VERSION 5.7 ;

  DIVIDERCHAR "/" ;
  BUSBITCHARS "[]" ;
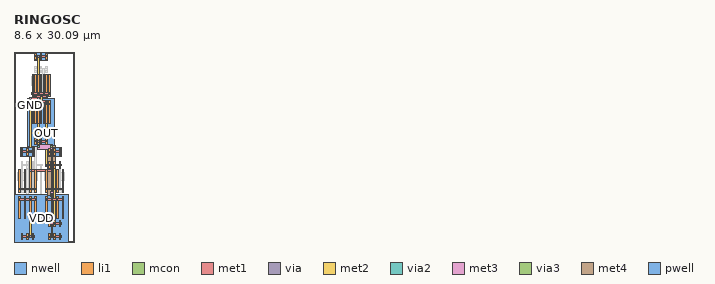
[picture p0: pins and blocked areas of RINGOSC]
MACRO RINGOSC
  CLASS BLOCK ;
  FOREIGN RINGOSC ;
  ORIGIN 0.000 0.000 ;
  SIZE 8.600 BY 30.090 ;
  PIN VDD
    ANTENNADIFFAREA 5.147100 ;
    PORT
      LAYER nwell ;
        RECT 2.150 15.120 6.450 22.680 ;
        RECT 0.000 0.000 8.600 7.560 ;
      LAYER li1 ;
        RECT 2.885 18.815 3.135 22.345 ;
        RECT 3.745 18.815 3.995 22.345 ;
        RECT 4.605 18.815 4.855 22.345 ;
        RECT 5.465 18.815 5.715 22.345 ;
        RECT 3.315 15.455 3.565 16.465 ;
        RECT 4.175 15.455 4.425 16.465 ;
        RECT 5.035 15.455 5.285 16.465 ;
        RECT 0.735 3.695 0.985 7.225 ;
        RECT 1.595 3.695 1.845 7.225 ;
        RECT 2.455 3.695 2.705 7.225 ;
        RECT 3.315 3.695 3.565 7.225 ;
        RECT 5.035 3.695 5.285 7.225 ;
        RECT 5.895 3.695 6.145 7.225 ;
        RECT 6.755 3.695 7.005 7.225 ;
        RECT 7.615 3.695 7.865 7.225 ;
        RECT 1.165 0.335 1.415 1.345 ;
        RECT 2.025 0.335 2.275 1.345 ;
        RECT 2.885 0.335 3.135 1.345 ;
        RECT 5.465 0.335 5.715 1.345 ;
        RECT 6.325 0.335 6.575 1.345 ;
        RECT 7.185 0.335 7.435 1.345 ;
      LAYER mcon ;
        RECT 2.925 21.755 3.095 21.925 ;
        RECT 3.785 21.755 3.955 21.925 ;
        RECT 4.645 21.755 4.815 21.925 ;
        RECT 5.505 21.755 5.675 21.925 ;
        RECT 3.355 15.875 3.525 16.045 ;
        RECT 4.215 15.875 4.385 16.045 ;
        RECT 5.075 15.875 5.245 16.045 ;
        RECT 0.775 6.635 0.945 6.805 ;
        RECT 1.635 6.635 1.805 6.805 ;
        RECT 2.495 6.635 2.665 6.805 ;
        RECT 3.355 6.635 3.525 6.805 ;
        RECT 5.075 6.635 5.245 6.805 ;
        RECT 5.935 6.635 6.105 6.805 ;
        RECT 6.795 6.635 6.965 6.805 ;
        RECT 7.655 6.635 7.825 6.805 ;
        RECT 1.205 0.755 1.375 0.925 ;
        RECT 2.065 0.755 2.235 0.925 ;
        RECT 2.925 0.755 3.095 0.925 ;
        RECT 5.505 0.755 5.675 0.925 ;
        RECT 6.365 0.755 6.535 0.925 ;
        RECT 7.225 0.755 7.395 0.925 ;
      LAYER met1 ;
        RECT 2.840 21.700 5.760 21.980 ;
        RECT 3.270 15.820 5.330 16.100 ;
        RECT 0.690 6.580 3.610 6.860 ;
        RECT 4.990 6.580 7.910 6.860 ;
        RECT 2.420 3.640 6.180 3.920 ;
        RECT 1.120 0.700 3.180 0.980 ;
        RECT 5.420 0.700 7.480 0.980 ;
      LAYER via ;
        RECT 3.740 21.710 4.000 21.970 ;
        RECT 3.740 15.830 4.000 16.090 ;
        RECT 2.450 6.590 2.710 6.850 ;
        RECT 5.890 6.590 6.150 6.850 ;
        RECT 2.450 3.650 2.710 3.910 ;
        RECT 5.890 3.650 6.150 3.910 ;
        RECT 2.450 0.710 2.710 0.970 ;
        RECT 5.890 0.710 6.150 0.970 ;
      LAYER met2 ;
        RECT 3.730 14.935 4.010 22.000 ;
        RECT 2.440 0.680 2.720 6.880 ;
        RECT 5.880 0.680 6.160 7.745 ;
      LAYER via2 ;
        RECT 3.730 14.980 4.010 15.260 ;
        RECT 5.880 7.420 6.160 7.700 ;
      LAYER met3 ;
        RECT 3.705 14.720 6.085 15.520 ;
        RECT 5.755 7.160 6.185 7.960 ;
      LAYER via3 ;
        RECT 5.760 14.960 6.080 15.280 ;
        RECT 5.760 7.400 6.080 7.720 ;
      LAYER met4 ;
        RECT 5.330 7.395 6.510 15.285 ;
    END
  END VDD
  PIN OUT
    ANTENNAGATEAREA 1.890000 ;
    ANTENNADIFFAREA 1.764000 ;
    PORT
      LAYER li1 ;
        RECT 3.315 23.015 3.565 26.545 ;
        RECT 4.175 23.015 4.425 26.545 ;
        RECT 5.035 23.015 5.285 26.545 ;
        RECT 3.315 18.815 3.565 22.345 ;
        RECT 4.175 18.815 4.425 22.345 ;
        RECT 5.035 18.815 5.285 22.345 ;
        RECT 5.465 11.675 5.715 12.685 ;
        RECT 6.325 11.675 6.575 12.685 ;
        RECT 7.185 11.675 7.435 12.685 ;
        RECT 5.465 2.435 5.715 3.445 ;
        RECT 6.325 2.435 6.575 3.445 ;
        RECT 7.185 2.435 7.435 3.445 ;
      LAYER mcon ;
        RECT 3.355 23.015 3.525 23.185 ;
        RECT 4.215 23.015 4.385 23.185 ;
        RECT 5.075 23.015 5.245 23.185 ;
        RECT 3.355 22.175 3.525 22.345 ;
        RECT 4.215 22.175 4.385 22.345 ;
        RECT 5.075 22.175 5.245 22.345 ;
        RECT 5.505 12.095 5.675 12.265 ;
        RECT 6.365 12.095 6.535 12.265 ;
        RECT 7.225 12.095 7.395 12.265 ;
        RECT 5.505 2.855 5.675 3.025 ;
        RECT 6.365 2.855 6.535 3.025 ;
        RECT 7.225 2.855 7.395 3.025 ;
      LAYER met1 ;
        RECT 3.270 22.960 5.330 23.240 ;
        RECT 3.270 22.120 5.330 22.400 ;
        RECT 5.000 12.040 7.480 12.320 ;
        RECT 5.420 2.800 7.480 3.080 ;
      LAYER via ;
        RECT 4.170 22.970 4.430 23.230 ;
        RECT 4.170 22.130 4.430 22.390 ;
        RECT 5.030 22.130 5.290 22.390 ;
        RECT 5.030 12.050 5.290 12.310 ;
        RECT 6.320 12.050 6.580 12.310 ;
        RECT 6.320 2.810 6.580 3.070 ;
      LAYER met2 ;
        RECT 4.160 22.100 4.440 23.260 ;
        RECT 5.020 12.020 5.300 22.420 ;
        RECT 6.310 2.780 6.590 12.340 ;
    END
  END OUT
  PIN GND
    ANTENNADIFFAREA 5.147100 ;
    PORT
      LAYER pwell ;
        RECT 3.225 28.710 5.375 30.090 ;
        RECT 1.075 13.590 3.225 14.970 ;
        RECT 5.375 13.590 7.525 14.970 ;
      LAYER li1 ;
        RECT 3.315 28.895 3.565 29.905 ;
        RECT 4.175 28.895 4.425 29.905 ;
        RECT 5.035 28.895 5.285 29.905 ;
        RECT 2.885 23.015 3.135 26.545 ;
        RECT 3.745 23.015 3.995 26.545 ;
        RECT 4.605 23.015 4.855 26.545 ;
        RECT 5.465 23.015 5.715 26.545 ;
        RECT 1.165 13.775 1.415 14.785 ;
        RECT 2.025 13.775 2.275 14.785 ;
        RECT 2.885 13.775 3.135 14.785 ;
        RECT 5.465 13.775 5.715 14.785 ;
        RECT 6.325 13.775 6.575 14.785 ;
        RECT 7.185 13.775 7.435 14.785 ;
        RECT 0.735 7.895 0.985 11.425 ;
        RECT 1.595 7.895 1.845 11.425 ;
        RECT 2.455 7.895 2.705 11.425 ;
        RECT 3.315 7.895 3.565 11.425 ;
        RECT 5.035 7.895 5.285 11.425 ;
        RECT 5.895 7.895 6.145 11.425 ;
        RECT 6.755 7.895 7.005 11.425 ;
        RECT 7.615 7.895 7.865 11.425 ;
      LAYER mcon ;
        RECT 3.355 29.315 3.525 29.485 ;
        RECT 4.215 29.315 4.385 29.485 ;
        RECT 5.075 29.315 5.245 29.485 ;
        RECT 2.925 23.435 3.095 23.605 ;
        RECT 3.785 23.435 3.955 23.605 ;
        RECT 4.645 23.435 4.815 23.605 ;
        RECT 5.505 23.435 5.675 23.605 ;
        RECT 1.205 14.195 1.375 14.365 ;
        RECT 2.065 14.195 2.235 14.365 ;
        RECT 2.925 14.195 3.095 14.365 ;
        RECT 5.505 14.195 5.675 14.365 ;
        RECT 6.365 14.195 6.535 14.365 ;
        RECT 7.225 14.195 7.395 14.365 ;
        RECT 0.775 8.315 0.945 8.485 ;
        RECT 1.635 8.315 1.805 8.485 ;
        RECT 2.495 8.315 2.665 8.485 ;
        RECT 3.355 8.315 3.525 8.485 ;
        RECT 5.075 8.315 5.245 8.485 ;
        RECT 5.935 8.315 6.105 8.485 ;
        RECT 6.795 8.315 6.965 8.485 ;
        RECT 7.655 8.315 7.825 8.485 ;
      LAYER met1 ;
        RECT 3.270 29.260 5.330 29.540 ;
        RECT 2.840 23.380 5.760 23.660 ;
        RECT 2.420 22.540 4.030 22.820 ;
        RECT 1.120 14.140 3.180 14.420 ;
        RECT 5.420 14.140 7.480 14.420 ;
        RECT 2.420 11.200 6.180 11.480 ;
        RECT 0.690 8.260 3.610 8.540 ;
        RECT 4.990 8.260 7.910 8.540 ;
      LAYER via ;
        RECT 3.740 29.270 4.000 29.530 ;
        RECT 3.740 23.390 4.000 23.650 ;
        RECT 2.450 22.550 2.710 22.810 ;
        RECT 3.740 22.550 4.000 22.810 ;
        RECT 2.450 14.150 2.710 14.410 ;
        RECT 5.890 14.150 6.150 14.410 ;
        RECT 2.450 11.210 2.710 11.470 ;
        RECT 5.890 11.210 6.150 11.470 ;
        RECT 2.450 8.270 2.710 8.530 ;
        RECT 5.890 8.270 6.150 8.530 ;
      LAYER met2 ;
        RECT 2.440 8.240 2.720 22.840 ;
        RECT 3.730 22.520 4.010 29.560 ;
        RECT 5.880 8.240 6.160 14.440 ;
    END
  END GND
  OBS
      LAYER pwell ;
        RECT 2.755 24.860 5.845 26.170 ;
        RECT 0.605 9.740 3.695 11.050 ;
        RECT 4.905 9.740 7.995 11.050 ;
      LAYER li1 ;
        RECT 3.315 26.795 3.565 27.805 ;
        RECT 4.175 26.795 4.425 27.805 ;
        RECT 5.035 26.795 5.285 27.805 ;
        RECT 3.315 17.555 3.565 18.565 ;
        RECT 4.175 17.555 4.425 18.565 ;
        RECT 5.035 17.555 5.285 18.565 ;
        RECT 1.165 11.675 1.415 12.685 ;
        RECT 2.025 11.675 2.275 12.685 ;
        RECT 2.885 11.675 3.135 12.685 ;
        RECT 1.165 7.895 1.415 11.425 ;
        RECT 2.025 7.895 2.275 11.425 ;
        RECT 2.885 7.895 3.135 11.425 ;
        RECT 1.165 3.695 1.415 7.225 ;
        RECT 2.025 3.695 2.275 7.225 ;
        RECT 2.885 3.695 3.135 7.225 ;
        RECT 1.165 2.435 1.415 3.445 ;
        RECT 2.025 2.435 2.275 3.445 ;
        RECT 2.885 2.435 3.135 3.445 ;
        RECT 4.175 2.855 4.425 12.265 ;
        RECT 5.465 7.895 5.715 11.425 ;
        RECT 6.325 7.895 6.575 11.425 ;
        RECT 7.185 7.895 7.435 11.425 ;
        RECT 5.465 3.695 5.715 7.225 ;
        RECT 6.325 3.695 6.575 7.225 ;
        RECT 7.185 3.695 7.435 7.225 ;
      LAYER mcon ;
        RECT 3.355 27.215 3.525 27.385 ;
        RECT 4.215 27.215 4.385 27.385 ;
        RECT 5.075 27.215 5.245 27.385 ;
        RECT 3.355 17.975 3.525 18.145 ;
        RECT 4.215 17.975 4.385 18.145 ;
        RECT 5.075 17.975 5.245 18.145 ;
        RECT 1.205 12.095 1.375 12.265 ;
        RECT 2.065 12.095 2.235 12.265 ;
        RECT 2.925 12.095 3.095 12.265 ;
        RECT 4.215 12.095 4.385 12.265 ;
        RECT 1.205 7.895 1.375 8.065 ;
        RECT 2.065 7.895 2.235 8.065 ;
        RECT 2.925 7.895 3.095 8.065 ;
        RECT 5.505 7.895 5.675 8.065 ;
        RECT 6.365 7.895 6.535 8.065 ;
        RECT 7.225 7.895 7.395 8.065 ;
        RECT 1.205 7.055 1.375 7.225 ;
        RECT 2.065 7.055 2.235 7.225 ;
        RECT 2.925 7.055 3.095 7.225 ;
        RECT 4.215 7.055 4.385 7.225 ;
        RECT 1.205 2.855 1.375 3.025 ;
        RECT 2.065 2.855 2.235 3.025 ;
        RECT 2.925 2.855 3.095 3.025 ;
        RECT 5.505 7.055 5.675 7.225 ;
        RECT 6.365 7.055 6.535 7.225 ;
        RECT 7.225 7.055 7.395 7.225 ;
        RECT 4.215 2.855 4.385 3.025 ;
      LAYER met1 ;
        RECT 3.270 27.160 5.330 27.440 ;
        RECT 3.270 17.920 5.330 18.200 ;
        RECT 1.120 12.040 4.470 12.320 ;
        RECT 1.120 7.840 3.600 8.120 ;
        RECT 5.420 7.840 7.480 8.120 ;
        RECT 1.120 7.000 3.180 7.280 ;
        RECT 4.130 7.000 7.480 7.280 ;
        RECT 1.120 2.800 4.470 3.080 ;
      LAYER via ;
        RECT 4.600 27.170 4.860 27.430 ;
        RECT 3.310 17.930 3.570 18.190 ;
        RECT 4.600 17.930 4.860 18.190 ;
        RECT 2.020 7.850 2.280 8.110 ;
        RECT 3.310 7.850 3.570 8.110 ;
        RECT 5.460 7.850 5.720 8.110 ;
        RECT 2.020 7.010 2.280 7.270 ;
        RECT 5.460 7.010 5.720 7.270 ;
      LAYER met2 ;
        RECT 2.010 6.980 2.290 8.140 ;
        RECT 3.300 7.820 3.580 18.220 ;
        RECT 4.590 17.900 4.870 27.460 ;
        RECT 5.450 6.980 5.730 8.140 ;
  END
END RINGOSC
END LIBRARY

